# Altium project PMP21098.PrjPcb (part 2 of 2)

## Sheet PMP21098_BlankSheet.SchDoc
size 431 x 279 mm; Date: Not shown in title block; ApprovedBy: Not shown in title block; CheckedBy: Not shown in title block; Author: Not shown in title block; CompanyName: Not shown in title block; Engineer: Not shown in title block; Organization: Not shown in title block; Address1: Not shown in title block; Address2: Not shown in title block; Address3: Not shown in title block; Address4: Not shown in title block; DocumentNumber: 2; Revision: Use project parameter SCH_Rev; SheetNumber: 2; SheetTotal: 3; PageSetup: Record=PageOptions¦CenterHorizontal=True¦CenterVertical=True¦PrintScale=1.00¦XCorrection=1.00¦YCorrection=1.00¦PrintKind=0¦BorderSize=5000000¦LeftOffset=0¦BottomOffset=0¦Orientation=2¦PaperLength=1000¦PaperWidth=1000¦Scale=100¦PaperSource=15¦PrintQuality=600¦MediaType=1¦DitherType=10¦PaperKind=Letter¦PrintScaleMode=1

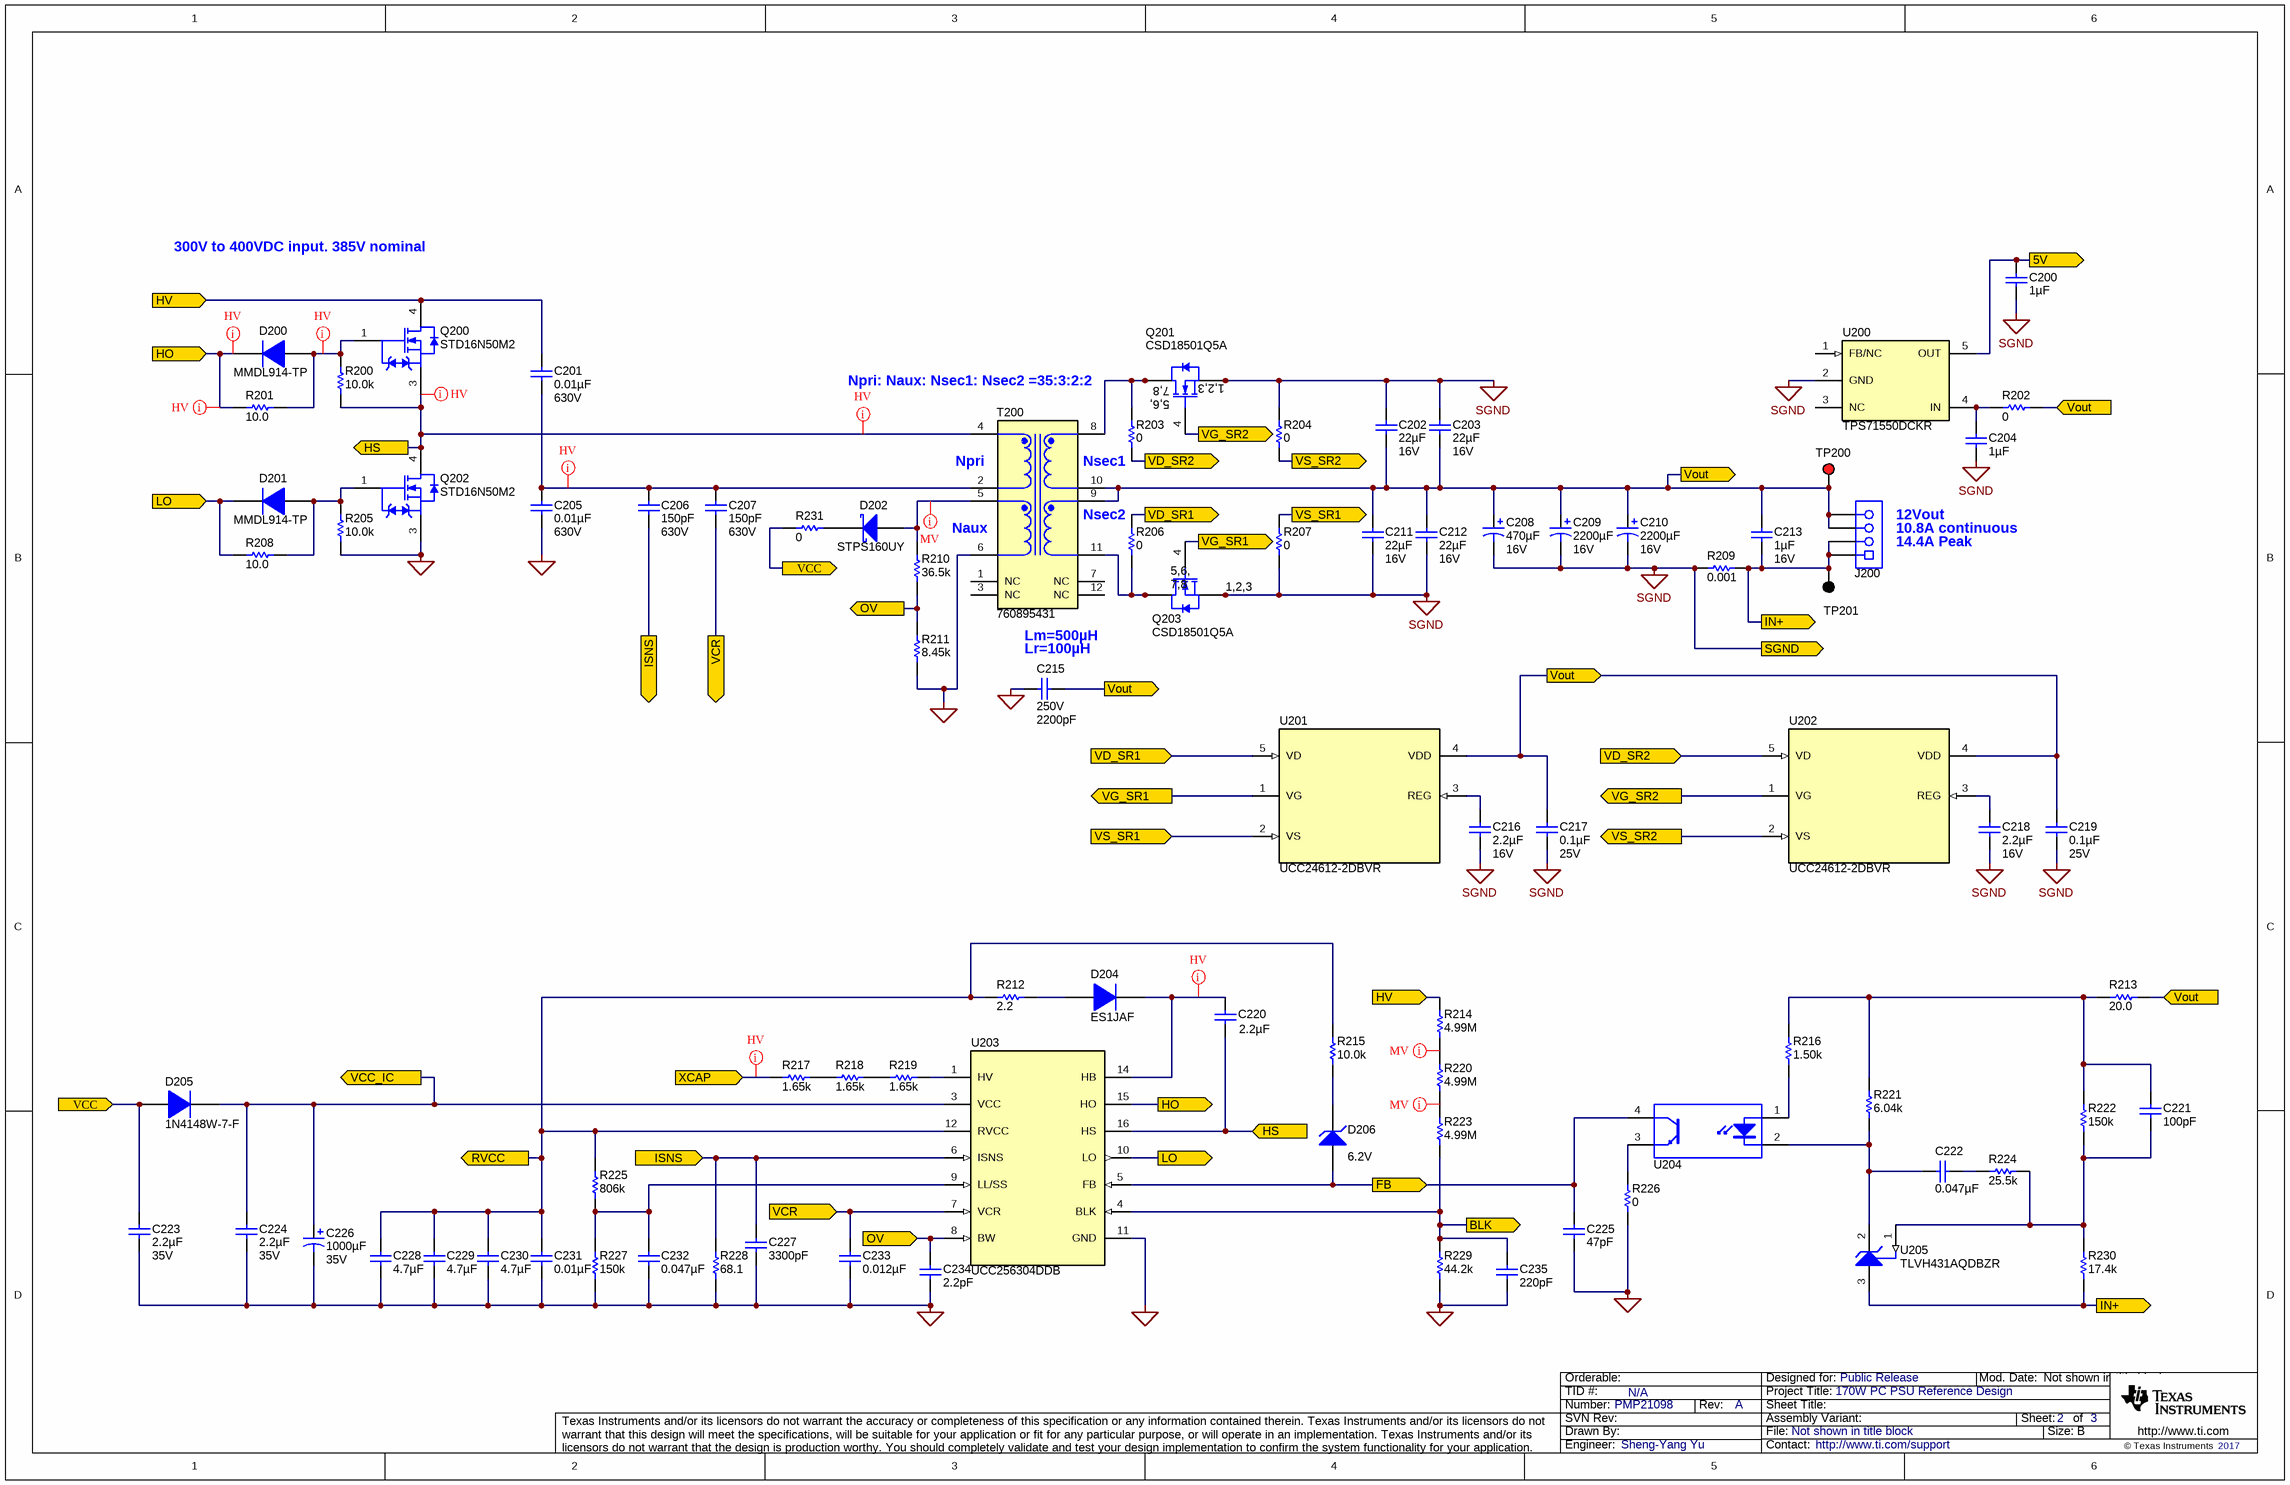
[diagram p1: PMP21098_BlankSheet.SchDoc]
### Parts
C200  ValueDisplayed: 1µF  [0603]  (hidden comment: C0603C105K4PACTU)
C201  ValueDisplayed: 0.01µF  Value2: 630V  [B32021_1300x400x900]  (hidden comment: B32621A6103K189)
C202  ValueDisplayed: 22µF  Value2: 16V  [1206_190]  (hidden comment: EMK316BB7226ML-T)
C203  ValueDisplayed: 22µF  Value2: 16V  [1206_190]  (hidden comment: EMK316BB7226ML-T)
C204  ValueDisplayed: 1µF  [1206]  (hidden comment: GRM319R61E105KC36D)
C205  ValueDisplayed: 0.01µF  Value2: 630V  [B32021_1300x400x900]  (hidden comment: B32621A6103K189)
C206  ValueDisplayed: 150pF  Value2: 630V  [1206]  (hidden comment: GRM31A5C2J151JW01D)
C207  ValueDisplayed: 150pF  Value2: 630V  [1206]  (hidden comment: GRM31A5C2J151JW01D)
C208  ValueDisplayed: 470µF  Value2: 16V  [PS_1000x1250]  (hidden comment: APSC160ELL471MJB5S)
C209  ValueDisplayed: 2200µF  Value2: 16V  [HW_1250x2000]  (hidden comment: EEU-FM1C222)
C210  ValueDisplayed: 2200µF  Value2: 16V  [HW_1250x2000]  (hidden comment: EEU-FM1C222)
C211  ValueDisplayed: 22µF  Value2: 16V  [1206_190]  (hidden comment: EMK316BB7226ML-T)
C212  ValueDisplayed: 22µF  Value2: 16V  [1206_190]  (hidden comment: EMK316BB7226ML-T)
C213  ValueDisplayed: 1µF  Value2: 16V  [0603]  (hidden comment: C0603C105K4PACTU)
C215  VDC_V: 250V  ValueDisplayed: 2200pF  [CAPRD1000W60D1000H1400]  (hidden comment: DE1E3KX222MA5BA01)
C216  ValueDisplayed: 2.2µF  Value2: 16V  [0603]  (hidden comment: 885012106018)
C217  ValueDisplayed: 0.1µF  Value2: 25V  [0603]  (hidden comment: 06033C104JAT2A)
C218  ValueDisplayed: 2.2µF  Value2: 16V  [0603]  (hidden comment: 885012106018)
C219  ValueDisplayed: 0.1µF  Value2: 25V  [0603]  (hidden comment: 06033C104JAT2A)
C220  ValueDisplayed: 2.2µF  [1206]  (hidden comment: C1206C225K4RACTU)
C221  ValueDisplayed: 100pF  [0603]  (hidden comment: 06035A101JAT2A)
C222  ValueDisplayed: 0.047µF  [0603]  (hidden comment: 06033C473JAT2A)
C223  ValueDisplayed: 2.2µF  Value2: 35V  [0603]  (hidden comment: GRM188R6YA225KA12D)
C224  ValueDisplayed: 2.2µF  Value2: 35V  [0603]  (hidden comment: GRM188R6YA225KA12D)
C225  ValueDisplayed: 47pF  [0603]  (hidden comment: GRM1885C1H470FA01J)
C226  ValueDisplayed: 1000µF  Value2: 35V  [B41896_1250x2500]  (hidden comment: EEU-FR1V102B)
C227  ValueDisplayed: 3300pF  [0603]  (hidden comment: GRM1885C1H332JA01D)
C228  ValueDisplayed: 4.7µF  [0603]  (hidden comment: GRM188R61C475KAAJ)
C229  ValueDisplayed: 4.7µF  [0603]  (hidden comment: GRM188R61C475KAAJ)
C230  ValueDisplayed: 4.7µF  [0603]  (hidden comment: GRM188R61C475KAAJ)
C231  ValueDisplayed: 0.01µF  [0603]  (hidden comment: 06031C103JAT2A)
C232  ValueDisplayed: 0.047µF  [0603]  (hidden comment: C1608X7R1H473K080AA)
C233  ValueDisplayed: 0.012µF  [0603]  (hidden comment: C0603C123J3GACTU)
C234  ValueDisplayed: 2.2pF  [0603]  (hidden comment: 06035A2R2CAT2A)
C235  ValueDisplayed: 220pF  [0603]  (hidden comment: GRM188R71H221KA01D)
D200  MMDL914-TP  [SOD-323]
D201  MMDL914-TP  [SOD-323]
D202  STPS160UY  [SMB]
D204  ES1JAF  [SMAF]
D205  1N4148W-7-F  [SOD-123]
D206  value 6.2V  [SOD-123]  (hidden comment: MMSZ5234B-7-F)
J200  ED120/4DS  [On-Shore_ED120_4DS]  (value not drawn)
Q200  STD16N50M2  [DPAK]
Q201  CSD18501Q5A  [DQJ0008A]
Q202  STD16N50M2  [DPAK]
Q203  CSD18501Q5A  [DQJ0008A]
R200  ValueDisplayed: 10.0k  [0805_HV]  (hidden comment: CRCW080510K0FKEA)
R201  ValueDisplayed: 10.0  [0603]  (hidden comment: CRCW060310R0FKEA)
R202  ValueDisplayed: 0  [0603]  (hidden comment: CRCW06030000Z0EA)
R203  ValueDisplayed: 0  [0402]  (hidden comment: CRCW04020000Z0ED)
R204  ValueDisplayed: 0  [0402]  (hidden comment: CRCW04020000Z0ED)
R205  ValueDisplayed: 10.0k  [0805_HV]  (hidden comment: CRCW080510K0FKEA)
R206  ValueDisplayed: 0  [0402]  (hidden comment: CRCW04020000Z0ED)
R207  ValueDisplayed: 0  [0402]  (hidden comment: CRCW04020000Z0ED)
R208  ValueDisplayed: 10.0  [0603]  (hidden comment: CRCW060310R0FKEA)
R209  ValueDisplayed: 0.001  [2010]  (hidden comment: CSNL2010FT1L00)
R210  ValueDisplayed: 36.5k  [0603]  (hidden comment: CRCW060336K5FKEA)
R211  ValueDisplayed: 8.45k  [0603]  (hidden comment: RC0603FR-078K45L)
R212  ValueDisplayed: 2.2  [0603]  (hidden comment: CRCW06032R20JNEA)
R213  ValueDisplayed: 20.0  [0603]  (hidden comment: CRCW060320R0FKEA)
R214  ValueDisplayed: 4.99M  [1206]  (hidden comment: CRCW12064M99FKEA)
R215  ValueDisplayed: 10.0k  [0603]  (hidden comment: ERJ-3EKF1002V)
R216  ValueDisplayed: 1.50k  [0603]  (hidden comment: CRCW06031K50FKEA)
R217  ValueDisplayed: 1.65k  [1206]  (hidden comment: CRCW12061K65FKEA)
R218  ValueDisplayed: 1.65k  [1206]  (hidden comment: CRCW12061K65FKEA)
R219  ValueDisplayed: 1.65k  [1206]  (hidden comment: CRCW12061K65FKEA)
R220  ValueDisplayed: 4.99M  [1206]  (hidden comment: CRCW12064M99FKEA)
R221  ValueDisplayed: 6.04k  [0603]  (hidden comment: CRCW06036K04FKEA)
R222  ValueDisplayed: 150k  [0603]  (hidden comment: CRCW0603150KFKEA)
R223  ValueDisplayed: 4.99M  [1206]  (hidden comment: CRCW12064M99FKEA)
R224  ValueDisplayed: 25.5k  [0603]  (hidden comment: CRCW060325K5FKEA)
R225  ValueDisplayed: 806k  [0603]  (hidden comment: CRCW0603806KFKEA)
R226  ValueDisplayed: 0  [0603]  (hidden comment: CRCW06030000Z0EA)
R227  ValueDisplayed: 150k  [0603]  (hidden comment: CRCW0603150KFKEA)
R228  ValueDisplayed: 68.1  [0603]  (hidden comment: CRCW060368R1FKEA)
R229  ValueDisplayed: 44.2k  [0603]  (hidden comment: CRCW060344K2FKEA)
R230  ValueDisplayed: 17.4k  [0603]  (hidden comment: CRCW060317K4FKEA)
R231  ValueDisplayed: 0  [5108]  (hidden comment: 5108)
T200  760895431  [Wurth_ETD34]
TP200  5000  [Keystone5000]  (value not drawn)
TP201  5001  [Keystone5001]  (value not drawn)
U200  TPS71550DCKR  [DCK0005A_N]
U201  UCC24612-2DBVR  [DBV0005A_N]
U202  UCC24612-2DBVR  [DBV0005A_N]
U203  UCC256304DDB  [DDB0014A]
U204  VO618A-3  [DIP-4]  (value not drawn)
U205  TLVH431AQDBZR  [DBZ0003A_N]

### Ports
5V (out), BLK (out), FB (out), HO (in), HO (out), HS, HS (in), HV (in), IN+ (out), ISNS (in), ISNS (out), LO (in), LO (out), OV (in), OV (out), RVCC (out), SGND (out), VCC (in), VCC (out), VCC_IC (out), VCR (in), VCR (out), VD_SR1 (in), VD_SR1 (out), VD_SR2 (in), VD_SR2 (out), VG_SR1 (out), VG_SR2 (out), Vout, Vout (in), Vout (out), VS_SR1 (in), VS_SR1 (out), VS_SR2 (out), XCAP (in)

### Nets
GND: C205.2 C215.2 C223.1 C224.1 C225.2 C226.2(-) C227.1 C228.2 C229.2 C230.2 C231.2 C232.2 C233.2 C234.2 C235.2 Q202.3(S) R205.1 R211.1 R226.1 R227.1 R228.1 R229.1 T200.6 U203.11(GND)
SGND: C200.2 C202.1 C203.1 C204.2 C208.2(-) C209.2(-) C210.2(-) C211.2 C212.2 C216.2 C217.2 C218.2 C219.2 Q201.1(S) Q201.2(S) Q201.3(S) Q203.1(S) Q203.2(S) Q203.3(S) R204.2 R207.1 R209.1 U200.2(GND) ; port SGND
5V: C200.1 U200.5(OUT) ; port 5V
BLK: C235.1 R223.1 R229.2 U203.4(BLK) ; port BLK
FB: C225.1 D206.2(A) U203.5(FB) U204.4(C) ; port FB
HO: D200.1(K) R201.1 U203.15(HO) ; port HO
HS: C220.2 Q200.3(S) Q202.4(D) R200.1 T200.4 U203.16(HS) ; port HS
HV: C201.1 Q200.4(D) R214.2 ; port HV
IN+: C213.1 J200.1 J200.2 R209.2 R230.1 TP201.1 U205.3(ANODE) ; port IN+
ISNS: C206.1 C227.2 R228.2 U203.6(ISNS) ; port ISNS
LO: D201.1(K) R208.1 U203.10(LO) ; port LO
OV: C234.1 R210.1 R211.2 U203.8(BW) ; port OV
RVCC: C228.1 C229.1 C230.1 C231.1 R212.1 R215.2 R225.2 U203.12(RVCC) ; port RVCC
VCC: C223.2 D205.2(A) R231.1 ; port VCC
VCC_IC: C224.2 C226.1(+) D205.1(K) U203.3(VCC) ; port VCC_IC
VCR: C207.2 C233.1 U203.7(VCR) ; port VCR
VD_SR1: R206.2 U201.5(VD) ; port VD_SR1
VD_SR2: R203.1 U202.5(VD) ; port VD_SR2
VG_SR1: Q203.4(G) U201.1(VG) ; port VG_SR1
VG_SR2: Q201.4(G) U202.1(VG) ; port VG_SR2
Vout: C202.2 C203.2 C208.1(+) C209.1(+) C210.1(+) C211.1 C212.1 C213.2 C215.1 C217.1 C219.1 J200.3 J200.4 R202.2 R213.1 T200.9 T200.10 TP200.1 U201.4(VDD) U202.4(VDD) ; port Vout
VS_SR1: R207.2 U201.2(VS) ; port VS_SR1
VS_SR2: R204.1 U202.2(VS) ; port VS_SR2
XCAP: R217.2 ; port XCAP
NetC201_2: C201.2 C205.1 C206.2 C207.1 T200.2
NetC204_1: C204.1 R202.1 U200.4(IN)
NetC216_1: C216.1 U201.3(REG)
NetC218_1: C218.1 U202.3(REG)
NetC220_1: C220.1 D204.1(K) U203.14(HB)
NetC221_1: C221.1 R213.2 R216.2 R221.2 R222.2
NetC221_2: C221.2 R222.1 R224.2 R230.2 U205.1(REF)
NetC222_1: C222.1 R224.1
NetC222_2: C222.2 R221.1 U204.2(K) U205.2(CATHODE)
NetC232_1: C232.1 R225.1 R227.2 U203.9(LL/SS)
NetD200_2: D200.2(A) Q200.1(G) R200.2 R201.2
NetD201_2: D201.2(A) Q202.1(G) R205.2 R208.2
NetD202_1: D202.1(K) R231.2
NetD202_2: D202.2(A) R210.2 T200.5
NetD204_2: D204.2(A) R212.2
NetD206_1: D206.1(K) R215.1
NetQ201_5: Q201.5(D) Q201.6(D) Q201.7(D) Q201.8(D) Q201.9(D) R203.2 T200.8
NetQ203_5: Q203.5(D) Q203.6(D) Q203.7(D) Q203.8(D) Q203.9(D) R206.1 T200.11
NetR214_1: R214.1 R220.2
NetR216_1: R216.1 U204.1(A)
NetR217_1: R217.1 R218.2
NetR218_1: R218.1 R219.2
NetR219_1: R219.1 U203.1(HV)
NetR220_1: R220.1 R223.2
NetR226_2: R226.2 U204.3(E)

Not connected (* = marked no-connect by the designer): T200 1(NC) 3(NC) 7(NC) 12(NC); U200 1(FB/NC) 3(NC)

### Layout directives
net class HV: HO, HS, NetC201_2, NetC220_1, NetD200_2, XCAP
net class MV: NetD202_2, NetR214_1, NetR220_1

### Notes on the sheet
- 300V to 400VDC input. 385V nominal
- Npri: Naux: Nsec1: Nsec2 =35:3:2:2
- (near T200) Npri
- Nsec1
- (near T200) Naux
- Nsec2
- (near J200) 12Vout
- (near J200) 10.8A continuous
- (near J200) 14.4A Peak
- Lm=500µH
- Lr=100µH

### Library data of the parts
C200 C213 = C0603C105K4PACTU: CAP, CERM, 1uF, 16V, +/-10%, X5R, 0603; Manufacturer: Kemet; Polarized: N; CompType: Capacitor; U/M: EA; Cap_F: 0.000001; Tolerance_%: 10; Value1: Unknown; VDC_V: 16; TaMin_C: -55; TaMax_C: 85
C201 C205 = B32021A3332M289: CAP FILM 10000PF 10% 630VDC RAD; Manufacturer: EPCOS (TDK); Polarized: N; CompType: Capacitor; Value: 0.01uF; U/M: EA; Tolerance_%: 20; Value1: Unknown; VDC_V: 630; TaMin_C: -40; TaMax_C: 110; SizeAreaWB_mm2: 90; SizeArea_mm2: 52; SizeX_mm: 13; SizeY_mm: 4; SizeZ_mm: 9; AEC Category: Q200; AEC Qualified: Y; AEC Grade: 2
C202 C203 C211 C212 = EMK316BB7226ML-T: CAP, CERM, 22 µF, 16 V,+/- 20%, X7R, 1206; Manufacturer: Taiyo Yuden; Polarized: N; CompType: Capacitor; Value: 22uF; U/M: EA; Cap_F: 0.000022; Tolerance_%: 20; VDC_V: 16; TaMin_C: -55; TaMax_C: 125; Cap_Case: 1206; SizeArea_mm2: 5.12; SizeAreaWB_mm2: 10.92; SizeX_mm: 3.2; SizeY_mm: 1.6; SizeZ_mm: 1.9; AEC Category: Q200
C204 = GRM319R61E105KC36D: CAP, CERM, 1 µF, 25 V,+/- 10%, X5R, 1206; Manufacturer: MuRata; Polarized: N; CompType: Capacitor; Value: 1uF; U/M: EA; Cap_F: 0.000001; Tolerance_%: 10; ESR_ohm: 0.01; Value1: 0.01 ohm; VDC_V: 25; Value2: 25V; TaMin_C: -55; TaMax_C: 85; SizeArea_mm2: 5.12; SizeAreaWB_mm2: 10.92; SizeX_mm: 3.2; SizeY_mm: 1.6; SizeZ_mm: 1.35; AEC Category: Q200
C206 = GRM31A5C2J151JW01D: CAP, CERM, 150 pF, 630 V, +/- 5%, C0G/NP0, 1206; Manufacturer: MuRata; Polarized: N; CompType: Capacitor; Value: 150pF; U/M: EA; Cap_F: 0.00000000015; Tolerance_%: 5; Value1: Unknown; VDC_V: 630; TaMin_C: -55; TaMax_C: 125; SizeArea_mm2: 5.12; SizeAreaWB_mm2: 10.92; SizeX_mm: 3.2; SizeY_mm: 1.6; SizeZ_mm: 1.35; AEC Category: Q200
C207 = GRM31A5C2J151JW01D: CAP, CERM, 150 pF, 630 V,+/- 5%, C0G/NP0, 1206; Manufacturer: MuRata; Polarized: N; CompType: Capacitor; Value: 150pF; U/M: EA; Cap_F: 0.00000000015; Tolerance_%: 5; VDC_V: 630; TaMin_C: -55; TaMax_C: 125; SizeArea_mm2: 5.12; SizeAreaWB_mm2: 10.92; SizeX_mm: 3.2; SizeY_mm: 1.6; SizeZ_mm: 1.35; AEC Category: Q200
C208 = APS-160ELL331MJC5S: CAP ALUM POLY 470UF 20% 16V T/H; Manufacturer: Chemi-Con; Polarized: Y; CompType: Capacitor; U/M: EA; Cap_F: 0.00033; Tolerance_%: 20; Value1: 0.014 ohm; VDC_V: 16; ESR_ohm: 0.014; IRMS_A: 5.05; TaMin_C: -55; TaMax_C: 105; SizeAreaWB_mm2: 144; SizeArea_mm2: 100; SizeX_mm: 10; SizeZ_mm: 14; AEC Category: Q200; Green_Lifecycle: Active; Green_REACh: Passed
C209 C210 = UHW1C222MHD: CAP ALUM 2200UF 20% 16V RADIAL; Manufacturer: Panasonic; Polarized: Y; CompType: Capacitor; Cap_F: 0.0022; Tolerance_%: 20; VDC_V: 16; ESR_ohm: 0.016; IRMS_A: 2.6; TaMin_C: -40; TaMax_C: 105; Cap_Case: 12.5x20mm; SizeAreaWB_mm2: 210.25; SizeArea_mm2: 156.25; SizeX_mm: 12.5; SizeZ_mm: 22; AEC Category: Q200
C215 = CMP-0009602-2: CAP, CERM, 2200 pF, 250 V, +/- 20%, E, Disc 10x8mm; Manufacturer: MuRata; TaMin_C: -25°C; Polarized: N; SizeAreaWB_mm2: 120; Value1: Unknown; U/M: EA; Value: 2200pF; TaMax_C: 85°C; SizeZ_mm: 14; SizeX_mm: 10; SizeY_mm: 8; SizeArea_mm2: 80; CompType: Capacitor; Cap_F: 2.2nF; AEC Category: Q200
C216 C218 = 885012106018: CAP, CERM, 2.2 µF, 16 V,+/- 20%, X5R, 0603; Manufacturer: Wurth Elektronik; Polarized: N; CompType: Capacitor; Value: 2.2uF; U/M: EA; Cap_F: 0.0000022; Tolerance_%: 20; VDC_V: 16; TaMin_C: -55; TaMax_C: 85; SizeArea_mm2: 1.28; SizeAreaWB_mm2: 4.68; SizeX_mm: 1.6; SizeY_mm: 0.8; SizeZ_mm: 1; AEC Category: Q200; Green_Lifecycle: Not Set; Green_REACh: Incomplete
C217 C219 = 06033C104JAT2A: CAP, CERM, 0.1 µF, 25 V,+/- 5%, X7R, 0603; Manufacturer: AVX; Polarized: N; CompType: Capacitor; Value: 0.1uF; U/M: EA; Cap_F: 0.0000001; Tolerance_%: 5; ESR_ohm: 0.05; Value1: 0.05 ohm; VDC_V: 25; TaMin_C: -55; TaMax_C: 125; SizeArea_mm2: 1.28; SizeAreaWB_mm2: 4.68; SizeX_mm: 1.6; SizeY_mm: 0.8; SizeZ_mm: 1; AEC Category: Q200; Green_Lifecycle: Active; Green_REACh: Passed
C220 = C1206C225K4RACTU: CAP, CERM, 2.2 µF, 16 V, +/- 10%, X7R, 1206; Manufacturer: Kemet; Polarized: N; CompType: Capacitor; Value: 2.2uF; U/M: EA; Cap_F: 0.0000022; Tolerance_%: 10; ESR_ohm: 0.009; Value1: 0.009 ohm; VDC_V: 16; Value2: 16V; IRMS_A: 4.46; TaMin_C: -55; TaMax_C: 125; AEC Category: Q200; SizeArea_mm2: 5.12; SizeAreaWB_mm2: 10.92; SizeX_mm: 3.2; SizeY_mm: 1.6; SizeZ_mm: 1.35
C221 = 06035A101JAT2A: CAP, CERM, 100 pF, 50 V,+/- 5%, C0G/NP0, 0603; Manufacturer: AVX; Polarized: N; CompType: Capacitor; Value: 100pF; U/M: EA; Cap_F: 0.0000000001; Tolerance_%: 5; ESR_ohm: 0.119; Value1: 0.119 ohm; VDC_V: 50; Value2: 50V; TaMin_C: -55; TaMax_C: 125; SizeArea_mm2: 1.28; SizeAreaWB_mm2: 4.68; SizeX_mm: 1.6; SizeY_mm: 0.8; SizeZ_mm: 1; AEC Category: Q200; Green_Lifecycle: Active; Green_REACh: Passed
C222 = 06033C473JAT2A: CAP, CERM, 0.047 µF, 25 V,+/- 5%, X7R, 0603; Manufacturer: AVX; Polarized: N; CompType: Capacitor; Value: 0.047uF; U/M: EA; Cap_F: 0.000000047; Tolerance_%: 5; ESR_ohm: 0.052; Value1: 0.052 ohm; VDC_V: 25; Value2: 25V; TaMin_C: -55; TaMax_C: 125; SizeArea_mm2: 1.28; SizeAreaWB_mm2: 4.68; SizeX_mm: 1.6; SizeY_mm: 0.8; SizeZ_mm: 1; AEC Category: Q200; Green_Lifecycle: Active; Green_REACh: Passed
C223 C224 = GRM188R6YA225KA12D: CAP, CERM, 2.2 µF, 35 V, +/- 10%, X5R, 0603; Manufacturer: MuRata; Polarized: N; CompType: Capacitor; Value: 2.2uF; U/M: EA; Cap_F: 0.0000022; Tolerance_%: 10; Value1: Unknown; VDC_V: 35; TaMin_C: -55; TaMax_C: 85; AEC Category: Q200
C225 = GRM1885C1H470FA01J: CAP, CERM, 47 pF, 50 V, +/- 1%, C0G/NP0, 0603; Manufacturer: MuRata; Polarized: N; CompType: Capacitor; Value: 47pF; U/M: EA; Cap_F: 0.000000000047; Tolerance_%: 1; Value1: Unknown; VDC_V: 50; Value2: 50V; TaMin_C: -55; TaMax_C: 125; AEC Category: Q200
C226 = B41896C7687M000: CAP ALUM 1000UF 20% 35V RADIAL; Manufacturer: Panasonic; Polarized: Y; CompType: Capacitor; U/M: EA; Cap_F: 0.00068; Tolerance_%: 20; Value1: 0.041 ohm; VDC_V: 35; ESR_ohm: 0.041; IRMS_A: 2.28; TaMin_C: -55; TaMax_C: 125; Cap_Case: 12.5x25mm; SizeAreaWB_mm2: 210.25; SizeArea_mm2: 156.25; SizeX_mm: 12.5; SizeZ_mm: 27; AEC Category: Q200; AEC Grade: 1; Green_Lifecycle: Not Set; Green_REACh: Incomplete
C227 = GRM1885C1H332JA01D: CAP, CERM, 3300 pF, 50 V, +/- 5%, C0G/NP0, 0603; Manufacturer: MuRata; Polarized: N; CompType: Capacitor; Value: 3300pF; U/M: EA; Cap_F: 0.0000000033; Tolerance_%: 5; Value1: Unknown; VDC_V: 50; Value2: 50V; TaMin_C: -55; TaMax_C: 125; SizeArea_mm2: 1.28; SizeAreaWB_mm2: 4.68; SizeX_mm: 1.6; SizeY_mm: 0.8; SizeZ_mm: 1; AEC Category: Q200
C228-C230 = GRM188R61C475KAAJ: CAP, CERM, 4.7 µF, 16 V, +/- 10%, X5R, 0603; Manufacturer: MuRata; Polarized: N; CompType: Capacitor; Value: 4.7uF; U/M: EA; Cap_F: 0.0000047; Tolerance_%: 10; Value1: Unknown; VDC_V: 16; Value2: 16V; TaMin_C: -55; TaMax_C: 85; AEC Category: Q200
C231 = 06031C103JAT2A: CAP, CERM, 0.01 µF, 100 V,+/- 5%, X7R, 0603; Manufacturer: AVX; Polarized: N; CompType: Capacitor; Value: 0.01uF; U/M: EA; Cap_F: 0.00000001; Tolerance_%: 5; ESR_ohm: 0.098; Value1: 0.098 ohm; VDC_V: 100; Value2: 100V; TaMin_C: -55; TaMax_C: 125; SizeArea_mm2: 1.28; SizeAreaWB_mm2: 4.68; SizeX_mm: 1.6; SizeY_mm: 0.8; SizeZ_mm: 1; AEC Category: Q200; Green_Lifecycle: Active; Green_REACh: Passed
C232 = C1608X7R1H473K080AA: CAP, CERM, 0.047 µF, 50 V,+/- 10%, X7R, 0603; Manufacturer: TDK; Polarized: N; CompType: Capacitor; Value: 0.047uF; U/M: EA; Cap_F: 0.000000047; Tolerance_%: 10; ESR_ohm: 0.049007; Value1: 0.049007 ohm; VDC_V: 50; Value2: 50V; IRMS_A: 0.767528; TaMin_C: -55; TaMax_C: 125; SizeArea_mm2: 1.28; SizeAreaWB_mm2: 4.68; SizeX_mm: 1.6; SizeY_mm: 0.8; SizeZ_mm: 1; AEC Category: Q200; Green_Lifecycle: NRND; Green_REACh: Passed
C233 = C0603C123J3GACTU: CAP, CERM, 0.012 µF, 25 V,+/- 5%, C0G/NP0, 0603; Manufacturer: Kemet; Polarized: N; CompType: Capacitor; Value: 0.012uF; U/M: EA; Cap_F: 0.000000012; Tolerance_%: 5; VDC_V: 25; Value2: 25V; TaMin_C: -55; TaMax_C: 125; SizeArea_mm2: 1.28; SizeAreaWB_mm2: 4.68; SizeX_mm: 1.6; SizeY_mm: 0.8; SizeZ_mm: 1; AEC Category: Q200; Green_Lifecycle: Not Set; Green_REACh: Incomplete
C234 = 06035A2R2CAT2A: CAP, CERM, 2.2 pF, 50 V, +/- 11%, C0G/NP0, 0603; Manufacturer: AVX; Polarized: N; CompType: Capacitor; Value: 2.2pF; U/M: EA; Cap_F: 0.0000000000022; Tolerance_%: 11; ESR_ohm: 1.033; Value1: 1.033 ohm; VDC_V: 50; Value2: 50V; TaMin_C: -55; TaMax_C: 125; SizeArea_mm2: 1.28; SizeAreaWB_mm2: 4.68; SizeX_mm: 1.6; SizeY_mm: 0.8; SizeZ_mm: 1; AEC Category: Q200
C235 = GRM188R71H221KA01D: CAP, CERM, 220 pF, 50 V, +/- 10%, X7R, 0603; Manufacturer: MuRata; Polarized: N; CompType: Capacitor; Value: 220pF; U/M: EA; Cap_F: 0.00000000022; Tolerance_%: 10; Value1: Unknown; VDC_V: 50; Value2: 50V; TaMin_C: -55; TaMax_C: 125; AEC Category: Q200
D200 D201 = MMDL914-TP: Diode, Switching, 100 V, 0.2 A, SOD-323; Manufacturer: Micro Commercial Components; U/M: EA; Vf_V: 1; Value: 100V; Value1: 0.2A; Value2: 1V; Io_A: 0.2; Vr_V: 100; TJmax_C: 150; SizeAreaWB_mm2: 8.695; SizeArea_mm2: 3.645; SizeX_mm: 2.7; SizeY_mm: 1.35; AEC Category: Q101
D202 = STPS160UY: Diode, Schottky, 60 V, 1 A, AEC-Q101, SMB; Manufacturer: STMicroelectronics; U/M: EA; Vf_V: 0.67; Value: 60V; Value1: 1A; Value2: 0.67V; Io_A: 1; Vr_V: 60; TJmax_C: 150; AEC Category: Q101; AEC Qualified: Y; SizeAreaWB_mm2: 44.156; SizeArea_mm2: 21.336; SizeX_mm: 5.6; SizeY_mm: 3.81; SizeZ_mm: 2.6
D204 = ES1JAF: Diode, Ultrafast, 600 V, 1 A, AEC-Q101, SMAF; Manufacturer: Fairchild Semiconductor; U/M: EA; Vf_V: 1.7; Value: 600V; Value1: 1A; Value2: 1.7V; Io_A: 1; Vr_V: 600; TJmax_C: 150; AEC Category: Q101; AEC Qualified: Y
D205 = 1N4148W-7-F: Diode, Ultrafast, 100 V, 0.15 A, SOD-123; Manufacturer: Diodes Inc.; U/M: EA; Vf_V: 1.25; Value: 100V; Value1: 0.15A; Value2: 1.25V; Io_A: 0.15; Vr_V: 100; TJmax_C: 150; SizeAreaWB_mm2: 13.095; SizeArea_mm2: 6.545; SizeX_mm: 3.85; SizeY_mm: 1.7; SizeZ_mm: 1.35; AEC Category: Q101
D206 = MMSZ5234B-7-F: Diode, Zener, 6.2 V, 500 mW, SOD-123; Manufacturer: Diodes Inc.; SymbolCreator: a0412235; U/M: EA; Power_W: 0.5; Vz_V: 6.2; Value1: 0.5W; RJA_CperW: 350; SizeAreaWB_mm2: 13.095; SizeArea_mm2: 6.545; SizeX_mm: 3.85; SizeY_mm: 1.7; SizeZ_mm: 1.35; AEC Category: Q101
J200 = ED120/4DS: Terminal Block, 5.08 mm, 4x1, Brass, TH; Manufacturer: On-Shore Technology; SymbolCreator: a0411947; Pitch_mm: 5.08; Gender: Female; Shrouded: N; Row_Count: 1; Current_A: 15; Voltage_V: 300; Cert_CULUS: Y
Q200 Q202 = STD16N50M2: MOSFET, N-CH, 550 V, 13 A, DPAK; Manufacturer: STMicroelectronics; Alternate Manufacturer: None; SymbolCreator: Altium; U/M: EA; ChType: N; Value: 550V; VdsMax_V: 550; Value1: ? ohm; Value2: 19.5 nC; QgTyp_nC: 19.5; Vgs_V: 25; IdsMax_A: 13; SizeAreaWB_mm2: 101.7114; SizeArea_mm2: 64.8114; SizeX_mm: 9.91; SizeY_mm: 6.54; SizeZ_mm: 2.29; AEC Category: Q101; Green_Lifecycle: Active; Green_REACh: Passed
Q201 Q203 = CSD18501Q5A: MOSFET, N-CH, 40 V, 22 A, DQJ0008A (VSONP-8); Manufacturer: Texas Instruments; Alternate Manufacturer: None; U/M: EA; ChType: N; Value: 40V; VdsMax_V: 40; Value1: 0.0043 ohm; Rdson45_ohm: 0.0043; Value2: 20 nC; QgTyp_nC: 20; IdsMax_A: 22; SizeAreaWB_mm2: 55.2; SizeArea_mm2: 29.4; SizeX_mm: 6; SizeY_mm: 4.9; SizeZ_mm: 1.1; AEC Category: Q101
R200 R205 = CRCW080510K0FKEA: RES, 10.0 k, 1%, 0.125 W, 0805; Manufacturer: Vishay-Dale; CompType: Resistor; Value: 10.0k; Res_ohm: 10000; Value_Code: 10k0; Tolerance_%: 1; Power_W: 0.125; Value2: 0.125W; VDC_V: 150; TempCo: 100 ppm/C; SizeArea_mm2: 2.5; SizeX_mm: 2; SizeY_mm: 1.25; SizeZ_mm: 1.45; EIA_Code: E96; U/M: EA; AEC Category: Q200
R201 R208 = CRCW060310R0FKEA: RES, 10.0, 1%, 0.1 W, 0603; Manufacturer: Vishay-Dale; CompType: Resistor; Value: 10.0; Res_ohm: 10; Value_Code: 10R0; Tolerance_%: 1; Power_W: 0.1; Value2: 0.1W; VDC_V: 75; TempCo: 100 ppm/C; SizeArea_mm2: 1.28; SizeX_mm: 1.6; SizeY_mm: 0.8; EIA_Code: E96; U/M: EA; AEC Category: Q200
R202 R226 = CRCW06030000Z0EA: RES, 0, 5%, 0.1 W, 0603; Manufacturer: Vishay-Dale; CompType: Resistor; Value: 0; Value_Code: 0000; Tolerance_%: 5; Power_W: 0.1; Value2: 0.1W; VDC_V: 75; TempCo: 200 ppm/C; SizeArea_mm2: 1.28; SizeX_mm: 1.6; SizeY_mm: 0.8; SizeZ_mm: 1; EIA_Code: E24; U/M: EA; AEC Category: Q200; Green_Lifecycle: Active; Green_REACh: Passed
R203 R204 R206 R207 = CRCW04020000Z0ED: RES, 0, 5%, 0.063 W, 0402; Manufacturer: Vishay-Dale; CompType: Resistor; Value: 0; Value_Code: 0000; Tolerance_%: 5; Power_W: 0.063; Value2: 0.063W; VDC_V: 50; TempCo: 200 ppm/C; SizeArea_mm2: 0.5; SizeX_mm: 1; SizeZ_mm: 0.6; EIA_Code: E24; U/M: EA; AEC Category: Q200; Green_Lifecycle: Active; Green_REACh: Passed
R209 = CSNL2010FT1L00: RES, 0.001, 1%, 1.5 W, 2010; Manufacturer: Stackpole Electronics Inc; CompType: Resistor; Value: 0.001; Value_Code: 1L000; Tolerance_%: 1; Power_W: 1.5; Value2: 1.5W; TempCo: 50 ppm/C; SizeArea_mm2: 12.5; SizeX_mm: 5; SizeY_mm: 2.5; SizeZ_mm: 1.66; EIA_Code: E96; U/M: EA; AEC Category: Q200
R210 = CRCW060336K5FKEA: RES, 36.5 k, 1%, 0.1 W, 0603; Manufacturer: Vishay-Dale; CompType: Resistor; Value: 36.5k; Res_ohm: 36500; Value_Code: 36k5; Tolerance_%: 1; Power_W: 0.1; Value2: 0.1W; VDC_V: 75; TempCo: 100 ppm/C; SizeArea_mm2: 1.28; SizeX_mm: 1.6; SizeY_mm: 0.8; EIA_Code: E96; U/M: EA; AEC Category: Q200
R211 = RC0603FR-078K45L: RES, 8.45 k, 1%, 0.1 W, 0603; Manufacturer: Yageo America; CompType: Resistor; Value: 8.45k; Res_ohm: 8450; Value_Code: 8k45; Tolerance_%: 1; Power_W: 0.1; Value2: 0.1W; VDC_V: 150; TempCo: 200 ppm/C; SizeArea_mm2: 1.28; SizeX_mm: 1.6; SizeY_mm: 0.8; EIA_Code: E96; U/M: EA; AEC Category: Q200; AEC Qualified: N; Green_Lifecycle: Active; Green_REACh: Passed
R212 = CRCW06032R20JNEA: RES, 2.2, 5%, 0.1 W, 0603; Manufacturer: Vishay-Dale; CompType: Resistor; Value: 2.2; Value_Code: 2R20; Tolerance_%: 5; Power_W: 0.1; Value2: 0.1W; VDC_V: 75; TempCo: 200 ppm/C; EIA_Code: E24; U/M: EA
R213 = CRCW060320R0FKEA: RES, 20.0, 1%, 0.1 W, 0603; Manufacturer: Vishay-Dale; CompType: Resistor; Value: 20.0; Res_ohm: 20; Value_Code: 20R0; Tolerance_%: 1; Power_W: 0.1; Value2: 0.1W; VDC_V: 75; TempCo: 100 ppm/C; SizeArea_mm2: 1.28; SizeX_mm: 1.6; SizeY_mm: 0.8; EIA_Code: E96; U/M: EA; AEC Category: Q200; Green_Lifecycle: Active; Green_REACh: Passed
R214 R220 R223 = CRCW12064M99FKEA: RES, 4.99 M, 1%, 0.25 W, 1206; Manufacturer: Vishay-Dale; CompType: Resistor; Value: 4.99Meg; Res_ohm: 4990000; Value_Code: 4M99; Tolerance_%: 1; Power_W: 0.25; Value2: 0.25W; VDC_V: 200; TempCo: 100 ppm/C; EIA_Code: E96; U/M: EA; AEC Category: Q200; SizeArea_mm2: 5.12; SizeX_mm: 3.2; SizeY_mm: 1.6; SizeZ_mm: 1.35
R215 = ERJ-3EKF1002V: RES, 10.0 k, 1%, 0.1 W, 0603; Manufacturer: Panasonic; CompType: Resistor; Value: 10.0k; Res_ohm: 10000; Value_Code: 10k0; Tolerance_%: 1; Power_W: 0.1; Value2: 0.1W; VDC_V: 75; TempCo: 100 ppm/C; SizeArea_mm2: 1.28; SizeX_mm: 1.6; SizeY_mm: 0.8; EIA_Code: E96; U/M: EA; AEC Category: Q200; Green_Lifecycle: Active; Green_REACh: Passed
R216 = CRCW06031K50FKEA: RES, 1.50 k, 1%, 0.1 W, 0603; Manufacturer: Vishay-Dale; CompType: Resistor; Value: 1.50k; Res_ohm: 1500; Value_Code: 1k50; Tolerance_%: 1; Power_W: 0.1; Value2: 0.1W; VDC_V: 75; TempCo: 100 ppm/C; SizeArea_mm2: 1.28; SizeX_mm: 1.6; SizeY_mm: 0.8; EIA_Code: E96; U/M: EA; AEC Category: Q200; Green_Lifecycle: Active; Green_REACh: Passed
R217-R219 = CRCW12061K65FKEA: RES, 1.65 k, 1%, 0.25 W, 1206; Manufacturer: Vishay-Dale; CompType: Resistor; Value: 1.65k; Res_ohm: 1650; Value_Code: 1k65; Tolerance_%: 1; Power_W: 0.25; Value2: 0.25W; VDC_V: 200; TempCo: 100 ppm/C; EIA_Code: E96; U/M: EA; AEC Category: Q200; SizeArea_mm2: 5.12; SizeX_mm: 3.2; SizeY_mm: 1.6; SizeZ_mm: 1.35
R221 = CRCW06036K04FKEA: RES, 6.04 k, 1%, 0.1 W, 0603; Manufacturer: Vishay-Dale; CompType: Resistor; Value: 6.04k; Res_ohm: 6040; Value_Code: 6k04; Tolerance_%: 1; Power_W: 0.1; Value2: 0.1W; VDC_V: 75; TempCo: 100 ppm/C; EIA_Code: E96; U/M: EA; AEC Category: Q200
R222 R227 = CRCW0603150KFKEA: RES, 150 k, 1%, 0.1 W, 0603; Manufacturer: Vishay-Dale; CompType: Resistor; Value: 150k; Res_ohm: 150000; Tolerance_%: 1; Power_W: 0.1; Value2: 0.1W; VDC_V: 75; TempCo: 100 ppm/C; SizeArea_mm2: 1.28; SizeX_mm: 1.6; SizeY_mm: 0.8; EIA_Code: E96; U/M: EA; AEC Category: Q200; Green_Lifecycle: Active; Green_REACh: Passed
R224 = CRCW060325K5FKEA: RES, 25.5 k, 1%, 0.1 W, 0603; Manufacturer: Vishay-Dale; CompType: Resistor; Value: 25.5k; Res_ohm: 25500; Value_Code: 25k5; Tolerance_%: 1; Power_W: 0.1; Value2: 0.1W; VDC_V: 75; TempCo: 100 ppm/C; SizeArea_mm2: 1.28; SizeX_mm: 1.6; SizeY_mm: 0.8; EIA_Code: E96; U/M: EA; AEC Category: Q200; Green_Lifecycle: Active; Green_REACh: Passed
R225 = CRCW0603806KFKEA: RES, 806 k, 1%, 0.1 W, 0603; Manufacturer: Vishay-Dale; CompType: Resistor; Value: 806k; Res_ohm: 806000; Tolerance_%: 1; Power_W: 0.1; Value2: 0.1W; VDC_V: 75; TempCo: 100 ppm/C; SizeArea_mm2: 1.28; SizeX_mm: 1.6; SizeY_mm: 0.8; EIA_Code: E96; U/M: EA; AEC Category: Q200; Green_Lifecycle: Active; Green_REACh: Passed
R228 = CRCW060368R1FKEA: RES, 68.1, 1%, 0.1 W, 0603; Manufacturer: Vishay-Dale; CompType: Resistor; Value: 68.1; Value_Code: 68R1; Tolerance_%: 1; Power_W: 0.1; Value2: 0.1W; VDC_V: 75; TempCo: 100 ppm/C; SizeArea_mm2: 1.28; SizeX_mm: 1.6; SizeY_mm: 0.8; EIA_Code: E96; U/M: EA; AEC Category: Q200
R229 = CRCW060344K2FKEA: RES, 44.2 k, 1%, 0.1 W, 0603; Manufacturer: Vishay-Dale; CompType: Resistor; Value: 44.2k; Res_ohm: 44200; Value_Code: 44k2; Tolerance_%: 1; Power_W: 0.1; Value2: 0.1W; VDC_V: 75; TempCo: 100 ppm/C; SizeArea_mm2: 1.28; SizeX_mm: 1.6; SizeY_mm: 0.8; EIA_Code: E96; U/M: EA; AEC Category: Q200; Green_Lifecycle: Active; Green_REACh: Passed
R230 = CRCW060317K4FKEA: RES, 17.4 k, 1%, 0.1 W, 0603; Manufacturer: Vishay-Dale; CompType: Resistor; Value: 17.4k; Res_ohm: 17400; Value_Code: 17k4; Tolerance_%: 1; Power_W: 0.1; Value2: 0.1W; VDC_V: 75; TempCo: 100 ppm/C; SizeArea_mm2: 1.28; SizeX_mm: 1.6; SizeY_mm: 0.8; EIA_Code: E96; U/M: EA; AEC Category: Q200; Green_Lifecycle: Active; Green_REACh: Passed
R231 = 5108: RES, 0, 1%, 0.5 W, 1206; Manufacturer: Keystone; CompType: Resistor; Value: 0; Tolerance_%: 1; Power_W: 0.5; Value2: 0.5W; TempCo: ppm/C; SizeArea_mm2: 5.185; SizeX_mm: 3.05; SizeY_mm: 1.7; SizeZ_mm: 0.84; U/M: EA; AEC Category: Q200; AEC Qualified: N
T200 = CMP-0077669-1: Transformer, 600 uH, TH; Manufacturer: Wurth Elektronik; SizeAreaWB_mm2: 1444.0; SizeArea_mm2: 1296.0; AEC Qualified: N; Ns2toNp: 0.057; Lp: 600.0; AEC Category: Q200; Value: 600uH; SizeZ_mm: 26.0; Ind_H: 600µH; SizeY_mm: 36.0; LeakageInd_H: 100µH; Rsec2_ohm: 3.1m; DCR_ohm: 2.6d
TP200 = 5000: Test Point, Miniature, Red, TH; Manufacturer: Keystone; CompType: Test Point Loop; ContactFinish: Silver
TP201 = 5001: Test Point, Miniature, Black, TH; Manufacturer: Keystone; CompType: Test Point Loop; ContactFinish: Silver; Green_Lifecycle: Active; Green_REACh: Passed
U200 = TPS71533DCKR: 50 mA, 24 V, 3.2-uA Iq, Low-Dropout Linear Regulator in SC70 Package, DCK0005A (SOT-SC70-5); Manufacturer: Texas Instruments; SymbolCreator: a0799628; SizeArea_mm2: 4.2; SizeAreaWB_mm2: 9.3; SizeX_mm: 2.1; SizeY_mm: 2; SizeZ_mm: 1.1; CompType: IC; U/M: EA; Green_Lifecycle: Active; Green_REACh: Passed
U201 U202 = UCC24612-1DBVR: UCC24612-2DBV, DBV0005A (SOT-23-5); Alternate PartNumber: UCC24612-2DBVT; Manufacturer: Texas Instruments; SymbolCreator: Altium; SizeArea_mm2: 8.12; SizeAreaWB_mm2: 14.82; SizeX_mm: 2.8; SizeY_mm: 2.9; SizeZ_mm: 1.45; CompType: IC; U/M: EA
U203 = UCC25630DDB: Enhanced LLC Resonant Controller with Driver, DDB0014A; Manufacturer: Texas Instruments; SymbolCreator: Altium; CompType: IC; U/M: EA
U204 = VO618A: OPTOISOLATOR 5.3KV TRANS 4-DIP; Manufacturer: Vishay-Semiconductor; CTR (Min): 100%; CTR (Max): 200%; Voltage_Isolation_Vrms: 5300V; CompType: Optocoupler; SizeAreaWB_mm2: 71.064; SizeArea_mm2: 40.304; SizeX_mm: 8.8; SizeY_mm: 4.58; SizeZ_mm: 5
U205 = TLVH431AQDBZR: Low-Voltage Adjustable Precision Shunt Regulator, 80 mA, -40 to 125 degC, 3-pin SOT-23 (DBZ), Green (RoHS & no Sb/Br); Manufacturer: Texas Instruments; Alternate PartNumber: Equivalent; Initial Accuracy @ 25/deg C(%): 1; Iout/Iz(Max)(mA): 80; Rating: Catalog; SubFamily: Shunt Voltage Reference; Temp Coeff(Max)(ppm/ degree C): 129; VO Adj(Max)(V): 18; VO Adj(Min)(V): 1.24

## Sheet PMP21098_EVM_Hardware.SchDoc
size 431 x 279 mm; Date: Not shown in title block; ApprovedBy: Not shown in title block; CheckedBy: Not shown in title block; Author: Not shown in title block; CompanyName: Not shown in title block; Engineer: Not shown in title block; Organization: Not shown in title block; Address1: Not shown in title block; Address2: Not shown in title block; Address3: Not shown in title block; Address4: Not shown in title block; DocumentNumber: 3; Revision: Use project parameter SCH_Rev; SheetNumber: 3; SheetTotal: 3; PageSetup: Record=PageOptions¦CenterHorizontal=True¦CenterVertical=True¦PrintScale=1.00¦XCorrection=1.00¦YCorrection=1.00¦PrintKind=0¦BorderSize=5000000¦LeftOffset=0¦BottomOffset=0¦Orientation=2¦PaperLength=1000¦PaperWidth=1000¦Scale=100¦PaperSource=15¦PrintQuality=600¦MediaType=1¦DitherType=10¦PaperKind=Letter¦PrintScaleMode=1

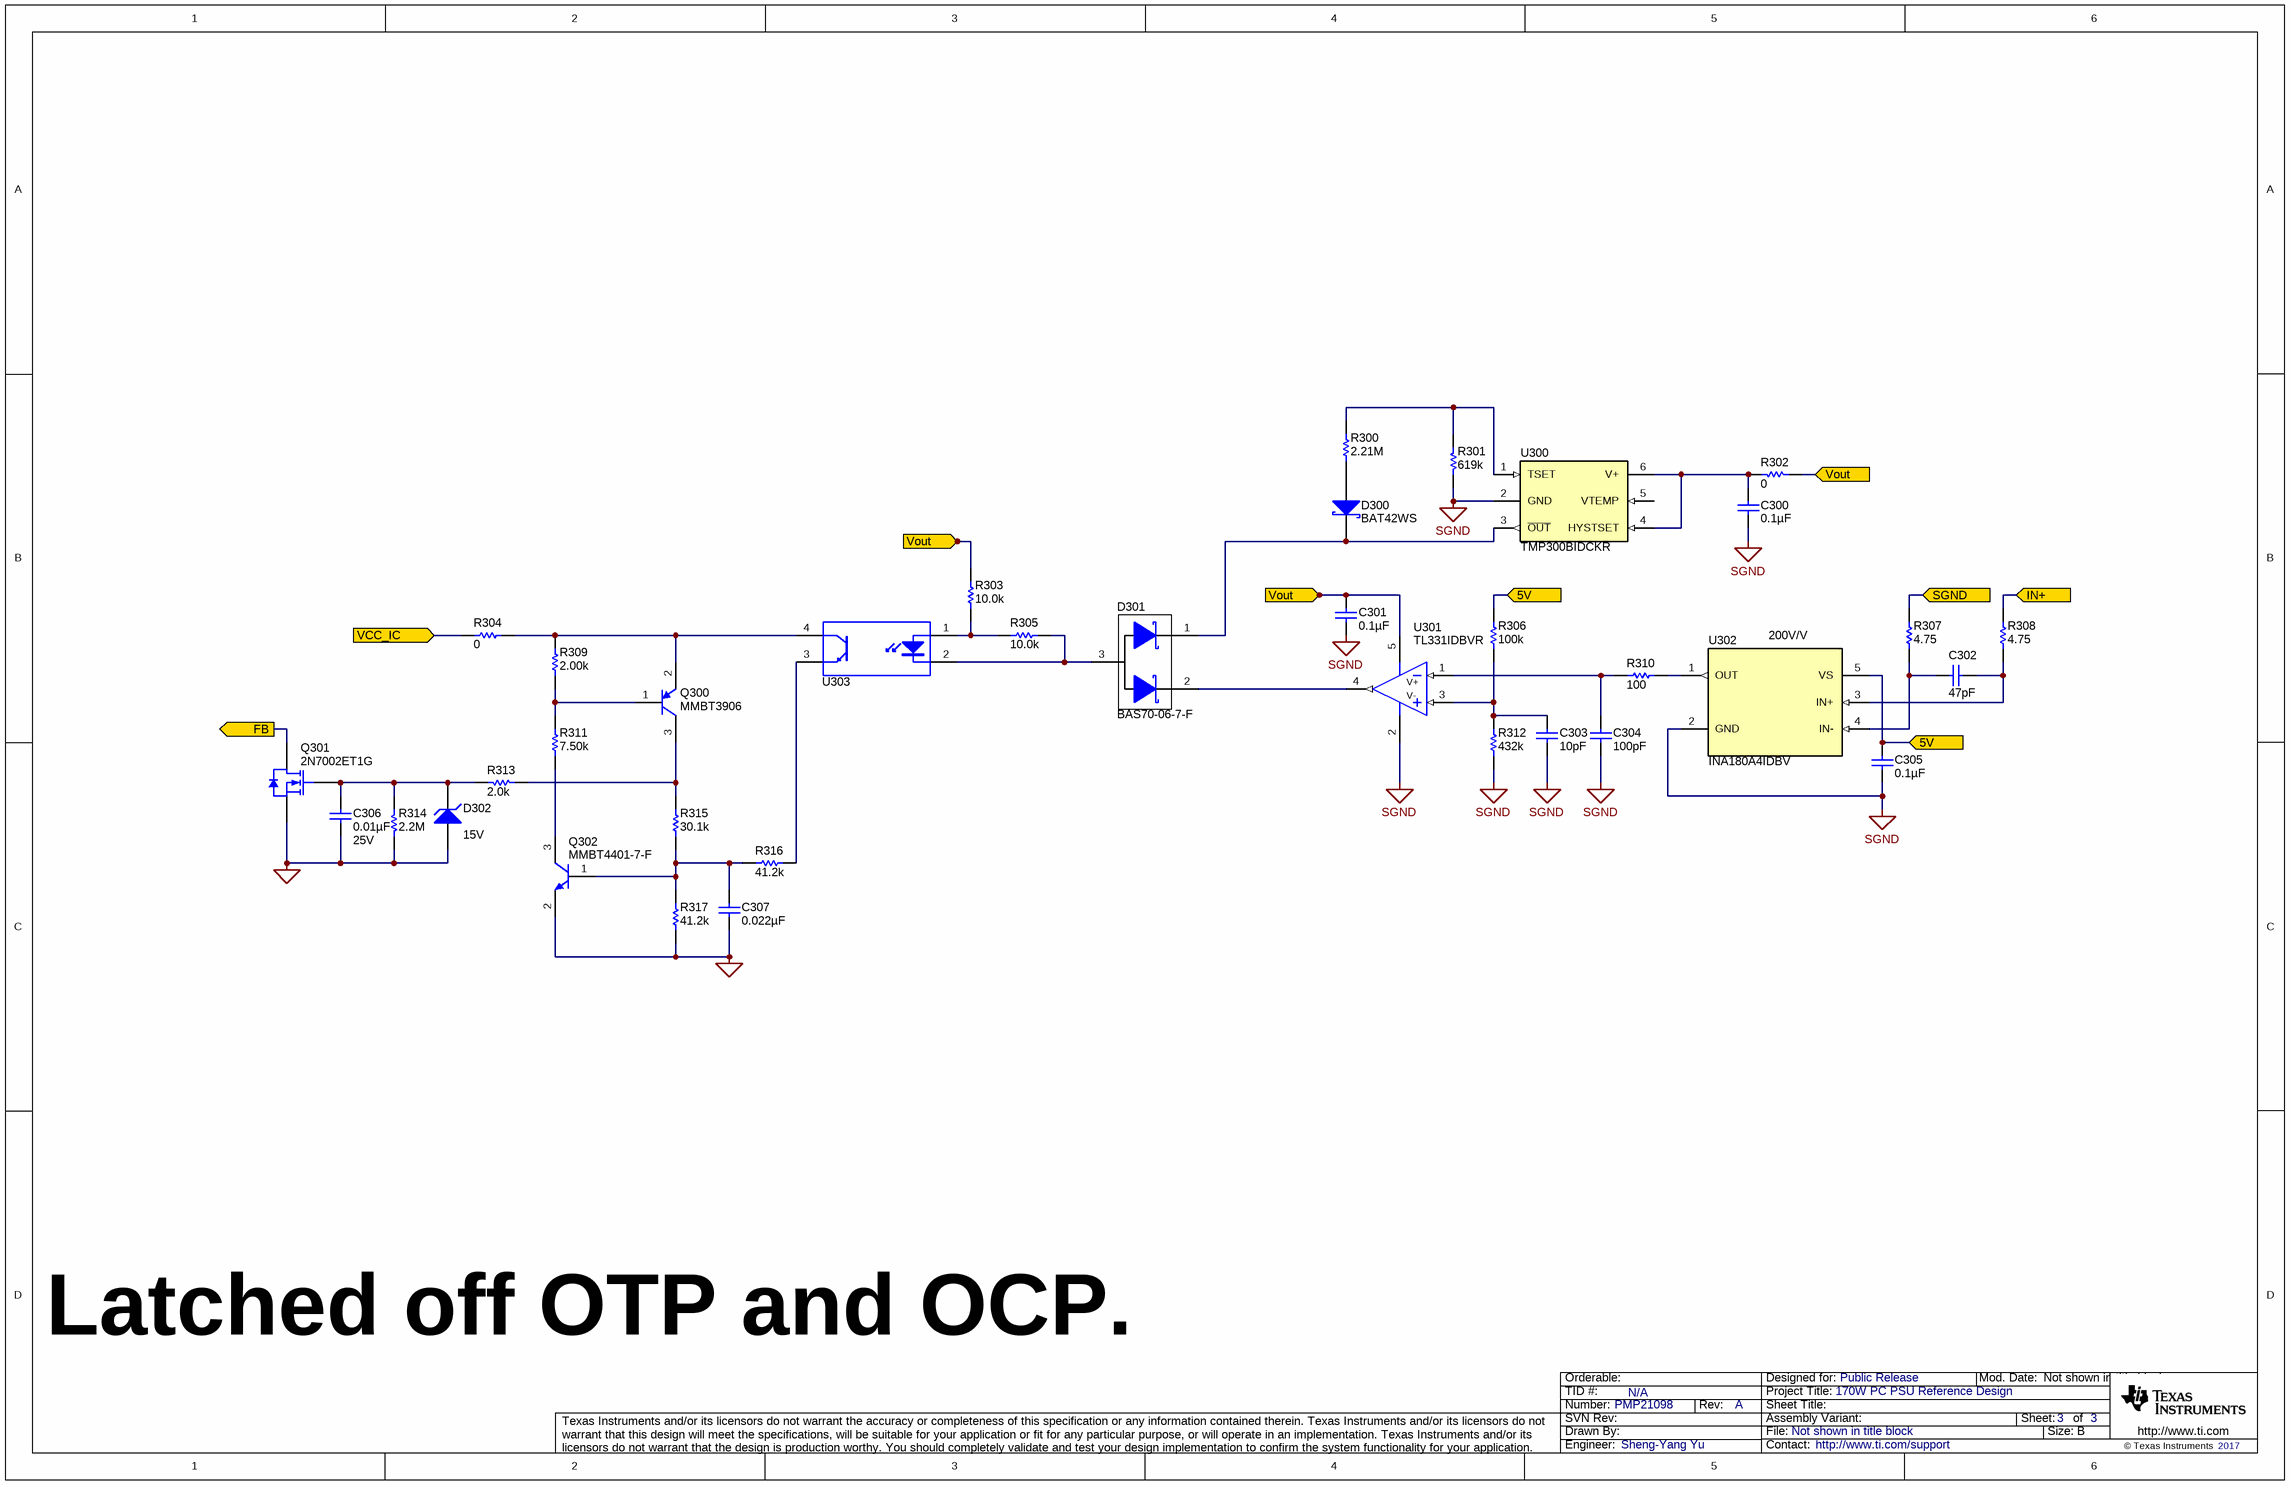
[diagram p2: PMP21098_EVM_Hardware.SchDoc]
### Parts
C300  ValueDisplayed: 0.1µF  [0402]  (hidden comment: GRM155R61C104KA88D)
C301  ValueDisplayed: 0.1µF  [0402]  (hidden comment: GRM155R61C104KA88D)
C302  ValueDisplayed: 47pF  [1206]  (hidden comment: 12067A470JAT2A)
C303  ValueDisplayed: 10pF  [0402]  (hidden comment: GRM1555C1H100RA01D)
C304  ValueDisplayed: 100pF  [0402]  (hidden comment: GRM1555C1H101JA01D)
C305  ValueDisplayed: 0.1µF  [0402]  (hidden comment: GRM155R61E104KA87D)
C306  ValueDisplayed: 0.01µF  Value2: 25V  [0603]  (hidden comment: C0603C103J3GECAUTO)
C307  ValueDisplayed: 0.022µF  [0603]  (hidden comment: C0603C223K5RACTU)
D300  BAT42WS  [sod-323]
D301  BAS70-06-7-F  [SOT-23]
D302  value 15V  [SOD-523]  (hidden comment: MM5Z15VT1G)
Q300  MMBT3906  [SOT-23]
Q301  2N7002ET1G  [SOT-23]
Q302  MMBT4401-7-F  [SOT-23]
R300  ValueDisplayed: 2.21M  [0603]  (hidden comment: CRCW06032M21FKEA)
R301  value 619k  [0402]  (hidden comment: CRCW0402619KFKED)
R302  value 0  [0402]  (hidden comment: ERJ-2GE0R00X)
R303  ValueDisplayed: 10.0k  [0603]  (hidden comment: CRCW060310K0FKEA)
R304  ValueDisplayed: 0  [0603]  (hidden comment: CRCW06030000Z0EA)
R305  ValueDisplayed: 10.0k  [0603]  (hidden comment: CRCW060310K0FKEA)
R306  ValueDisplayed: 100k  [0402]  (hidden comment: CRCW0402100KFKED)
R307  ValueDisplayed: 4.75  [0402]  (hidden comment: CRCW04024R75FKED)
R308  ValueDisplayed: 4.75  [0402]  (hidden comment: CRCW04024R75FKED)
R309  ValueDisplayed: 2.00k  [CPF0603]  (hidden comment: CPF0603B2K0E)
R310  ValueDisplayed: 100  [0402]  (hidden comment: ATC504L1000FTNCFT)
R311  ValueDisplayed: 7.50k  [0603]  (hidden comment: RC0603FR-077K5L)
R312  ValueDisplayed: 432k  [0603]  (hidden comment: CRCW0603432KFKEA)
R313  ValueDisplayed: 2.0k  [0603]  (hidden comment: RC0603JR-072KL)
R314  ValueDisplayed: 2.2M  [0603]  (hidden comment: CRCW06032M20JNEA)
R315  ValueDisplayed: 30.1k  [0603]  (hidden comment: CRCW060330K1FKEA)
R316  ValueDisplayed: 41.2k  [0603]  (hidden comment: CRCW060341K2FKEA)
R317  ValueDisplayed: 41.2k  [0603]  (hidden comment: CRCW060341K2FKEA)
U300  TMP300BIDCKR  [DCK0006A_N]
U301  TL331IDBVR  [DBV0005A_N]
U302  INA180A4IDBV  [DBV0005A_N]
U303  FOD817D  [DIP-4]  (value not drawn)

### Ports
5V (in), FB (out), IN+ (in), SGND (in), VCC_IC (in), Vout (in)

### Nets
GND: C306.2 C307.2 D302.2(A) Q301.2(S) Q302.2(E) R314.1 R317.1
SGND: C300.2 C301.2 C303.2 C304.2 C305.2 R301.1 R307.2 R312.1 U300.2(GND) U301.2(V-/GND) U302.2(GND) ; port SGND
5V: C305.1 R306.2 U302.5(VS) ; port 5V
FB: Q301.3(D) ; port FB
IN+: R308.2 ; port IN+
VCC_IC: R304.1 ; port VCC_IC
Vout: C301.1 R302.1 R303.2 U301.5(V+) ; port Vout
NetC300_1: C300.1 R302.2 U300.4(HYSTSET) U300.6(V+)
NetC302_1: C302.1 R308.1 U302.3(IN+)
NetC302_2: C302.2 R307.1 U302.4(IN-)
NetC303_1: C303.1 R306.1 R312.2 U301.3(IN+)
NetC304_1: C304.1 R310.2 U301.1(IN-)
NetC306_1: C306.1 D302.1(K) Q301.1(G) R313.2 R314.2
NetC307_1: C307.1 Q302.1(B) R315.1 R316.1 R317.2
NetD300_1: D300.1(K) D301.1(A) U300.3(~{OUT})
NetD300_2: D300.2(A) R300.1
NetD301_2: D301.2(K) U301.4(OUT)
NetD301_3: D301.3(A) R305.1 U303.2(K)
NetQ300_1: Q300.1(B) R309.1 R311.2
NetQ300_2: Q300.2(E) R304.2 R309.2 U303.4(C)
NetQ300_3: Q300.3(C) R313.1 R315.2
NetQ302_3: Q302.3(C) R311.1
NetR300_2: R300.2 R301.2 U300.1(TSET)
NetR303_1: R303.1 R305.2 U303.1(A)
NetR310_1: R310.1 U302.1(OUT)
NetR316_2: R316.2 U303.3(E)

Not connected (* = marked no-connect by the designer): U300 5(VTEMP)

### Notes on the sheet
- (near U302) 200V/V
- Latched off OTP and OCP.

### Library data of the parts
C300 C301 = GRM155R61C104KA88D: CAP, CERM, 0.1uF, 16V, +/-10%, X5R, 0402; Manufacturer: MuRata; Polarized: N; CompType: Capacitor; U/M: EA; Cap_F: 0.0000001; Tolerance_%: 10; Value1: Unknown; VDC_V: 16; TaMin_C: -55; TaMax_C: 85
C302 = 12067A470JAT2A: CAP, CERM, 47 pF, 500 V,+/- 5%, C0G/NP0, 1206; Manufacturer: AVX; Polarized: N; CompType: Capacitor; Value: 47pF; U/M: EA; Cap_F: 0.000000000047; Tolerance_%: 5; VDC_V: 500; Value2: 500V; TaMin_C: -55; TaMax_C: 125; SizeArea_mm2: 5.12; SizeAreaWB_mm2: 10.92; SizeX_mm: 3.2; SizeY_mm: 1.6; SizeZ_mm: 1.35; AEC Category: Q200; Green_Lifecycle: Not Set; Green_REACh: Incomplete
C303 = GRM1555C1H100RA01D: CAP, CERM, 10 pF, 50 V,+/- 4%, C0G/NP0, 0402; Manufacturer: MuRata; Polarized: N; CompType: Capacitor; Value: 10pF; U/M: EA; Cap_F: 0.00000000001; Tolerance_%: 4; VDC_V: 50; Value2: 50V; TaMin_C: -55; TaMax_C: 125; SizeArea_mm2: 0.5; SizeAreaWB_mm2: 3; SizeX_mm: 1; SizeZ_mm: 0.6; AEC Category: Q200
C304 = GRM1555C1H101JA01D: CAP, CERM, 100 pF, 50 V,+/- 5%, C0G/NP0, 0402; Manufacturer: MuRata; Polarized: N; CompType: Capacitor; Value: 100pF; U/M: EA; Cap_F: 0.0000000001; Tolerance_%: 5; VDC_V: 50; Value2: 50V; TaMin_C: -55; TaMax_C: 125; SizeArea_mm2: 0.5; SizeAreaWB_mm2: 3; SizeX_mm: 1; SizeZ_mm: 0.6; AEC Category: Q200; Green_Lifecycle: Active; Green_REACh: Passed
C305 = GRM155R61E104KA87D: CAP, CERM, 0.1 µF, 25 V, +/- 10%, X5R, 0402; Manufacturer: MuRata; Polarized: N; CompType: Capacitor; Value: 0.1uF; U/M: EA; Cap_F: 0.0000001; Tolerance_%: 10; Value1: Unknown; VDC_V: 25; Value2: 25V; TaMin_C: -55; TaMax_C: 85
C306 = C0603C103J3GECAUTO: CAP, CERM, 0.01 µF, 25 V,+/- 5%, C0G/NP0, AEC-Q200 Grade 1, 0603; Manufacturer: Kemet; Polarized: N; CompType: Capacitor; Value: 0.01uF; U/M: EA; Cap_F: 0.00000001; Tolerance_%: 5; VDC_V: 25; TaMin_C: -55; TaMax_C: 125; SizeArea_mm2: 1.28; SizeAreaWB_mm2: 4.68; SizeX_mm: 1.6; SizeY_mm: 0.8; SizeZ_mm: 1; AEC Category: Q200; AEC Qualified: Y
C307 = C0603C223K5RACTU: CAP, CERM, 0.022 µF, 50 V,+/- 10%, X7R, 0603; Manufacturer: Kemet; Polarized: N; CompType: Capacitor; Value: 0.022uF; U/M: EA; Cap_F: 0.000000022; Tolerance_%: 10; VDC_V: 50; Value2: 50V; TaMin_C: -55; TaMax_C: 125; SizeArea_mm2: 1.28; SizeAreaWB_mm2: 4.68; SizeX_mm: 1.6; SizeY_mm: 0.8; SizeZ_mm: 1; AEC Category: Q200; Green_Lifecycle: Active; Green_REACh: Passed
D300 = BAT42WS-7-F: Diode, Schottky, 30V, 0.2A, SOD-323; Manufacturer: Diodes Inc.; Value: 1V; U/M: EA; Vf_V: 1; Io_A: 0.2; Vr_V: 30
D301 = BAS70-06-7-F: Diode, Schottky, 70 V, 0.07 A, SOT-23; Manufacturer: Diodes Inc.; SymbolCreator: a0412235; U/M: EA; Vf_V: 1.7; Value: 70V; Value1: 0.07A; Value2: 1.7V; Io_A: 0.07; Vr_V: 70; SizeAreaWB_mm2: 14; SizeArea_mm2: 7.5; SizeX_mm: 2.5; SizeY_mm: 3; SizeZ_mm: 1.1; AEC Category: Q101; Green_Lifecycle: Not Set; Green_REACh: Incomplete
D302 = MM5Z5V6ST1G: DIODE ZENER 15V 200MW SOD523; Manufacturer: ON Semiconductor; SymbolCreator: a0412235; U/M: EA; Power_W: 0.5; Vz_V: 15; Value1: 0.5W; RJA_CperW: 250; SizeAreaWB_mm2: 5.13; SizeArea_mm2: 1.53; SizeX_mm: 1.7; SizeY_mm: 0.9; SizeZ_mm: 0.65; AEC Category: Q101
Q300 = MMBT3906, Fairchild Semiconductor: Transistor, PNP, 40 V, 0.2 A, SOT-23; CompType: BJT; PNP: 1; NPN: 0; Vceo_V: 40; Vcesat1_V: 0.25; Value: 40 V; IcRated_A: 0.2; Value1: 0.2 A; HfeMax: 300; TaMin_C: -55; TaMax_C: 150; SizeAreaWB_mm2: 14; SizeArea_mm2: 7.5; SizeX_mm: 2.5; SizeY_mm: 3; SizeZ_mm: 1.1; U/M: EA; AEC Category: Q101; Green_Lifecycle: Active; Green_REACh: Passed
Q301 = 2N7002ET1G: MOSFET, N-CH, 60V, 0.26A, SOT-23; Manufacturer: ON Semiconductor; Alternate Manufacturer: None; U/M: EA; ChType: N; VdsMax_V: 60; Value1: 3 ohm; Rdson45_Ohm: 3; Value2: 0.81 nC; QgTyp_nC: 0.81; Vgs_V: 20; IdsMax_A: 0.26
Q302 = MMBT4401-7-F, Diodes Inc.: Transistor, NPN, 40 V, 0.15 A, SOT-23; CompType: BJT; PNP: 0; NPN: 1; Vceo_V: 40; Vcesat1_V: 0.4; Value: 40 V; IcRated_A: 0.15; Value1: 0.15 A; HfeMax: 300; TaMin_C: -55; TaMax_C: 150; SizeAreaWB_mm2: 14; SizeArea_mm2: 7.5; SizeX_mm: 2.5; SizeY_mm: 3; SizeZ_mm: 1.1; U/M: EA; AEC Category: Q101; Green_Lifecycle: Active; Green_REACh: Passed
R300 = CRCW06032M21FKEA: RES, 2.21 M, 1%, 0.1 W, 0603; Manufacturer: Vishay-Dale; CompType: Resistor; Value: 2.21Meg; Res_ohm: 2210000; Value_Code: 2M21; Tolerance_%: 1; Power_W: 0.1; Value2: 0.1W; VDC_V: 75; TempCo: 100 ppm/C; SizeArea_mm2: 1.28; SizeX_mm: 1.6; SizeY_mm: 0.8; EIA_Code: E96; U/M: EA; AEC Category: Q200
R301 = CRCW0402619KFKED: RES, 619k ohm, 1%, 0.063W, 0402; Manufacturer: Vishay-Dale; CompType: Resistor; Res_ohm: 619000; Tolerance_%: 1; Power_W: 0.063; VDC_V: 50; TempCo: 100 ppm/C; EIA_Code: E96; U/M: EA
R302 = ERJ-2GE0R00X: RES, 0 ohm, 5%, 0.063W, 0402; Manufacturer: Panasonic; CompType: Resistor; Value_Code: 0000; Tolerance_%: 5; Power_W: 0.063; VDC_V: 50; TempCo: 600 ppm/C; EIA_Code: E24; U/M: EA
R303 R305 = CRCW060310K0FKEA: RES, 10.0 k, 1%, 0.1 W, 0603; Manufacturer: Vishay-Dale; CompType: Resistor; Value: 10.0k; Res_ohm: 10000; Value_Code: 10k0; Tolerance_%: 1; Power_W: 0.1; Value2: 0.1W; VDC_V: 75; TempCo: 100 ppm/C; SizeArea_mm2: 1.28; SizeX_mm: 1.6; SizeY_mm: 0.8; EIA_Code: E96; U/M: EA; AEC Category: Q200; Green_Lifecycle: Active; Green_REACh: Passed
R304 = CRCW06030000Z0EA: as R202 on sheet PMP21098_BlankSheet
R306 = CRCW0402100KFKED: RES, 100 k, 1%, 0.063 W, 0402; Manufacturer: Vishay-Dale; CompType: Resistor; Value: 100k; Res_ohm: 100000; Tolerance_%: 1; Power_W: 0.063; Value2: 0.063W; VDC_V: 50; TempCo: 100 ppm/C; SizeArea_mm2: 0.5; SizeZ_mm: 0.6; EIA_Code: E96; U/M: EA; AEC Category: Q200; Green_Lifecycle: Active; Green_REACh: Passed
R307 R308 = CRCW04024R75FKED: RES, 4.75, 1%, 0.063 W, 0402; Manufacturer: Vishay-Dale; CompType: Resistor; Value: 4.75; Value_Code: 4R75; Tolerance_%: 1; Power_W: 0.063; Value2: 0.063W; VDC_V: 50; TempCo: 100 ppm/C; SizeArea_mm2: 0.5; SizeZ_mm: 0.6; EIA_Code: E96; U/M: EA; AEC Category: Q200
R309 = CPF0603B2K0E: RES, 2.00 k, 0.1%, 0.063 W, 0603; Manufacturer: TE Connectivity; CompType: Resistor; Value: 2.00k; Res_ohm: 2000; Value_Code: 2k00; Tolerance_%: 0.1; Power_W: 0.063; Value2: 0.063W; VDC_V: 50; TempCo: 25 ppm/C; SizeArea_mm2: 1.24; SizeX_mm: 1.55; SizeY_mm: 0.8; SizeZ_mm: 0.55; EIA_Code: E192; U/M: EA; AEC Category: Q200; AEC Qualified: N; Green_Lifecycle: Active; Green_REACh: Passed
R310 = ATC504L1000FTNCFT: RES, 100, 1%, 0.125 W, AEC-Q200 Grade 1, 0402; Manufacturer: AT Ceramics; CompType: Resistor; Value: 100; Value_Code: 100R; Tolerance_%: 1; Power_W: 0.125; Value2: 0.125W; TempCo: ppm/C; SizeArea_mm2: 0.5; SizeZ_mm: 0.6; EIA_Code: E96; U/M: EA; AEC Category: Q200; AEC Qualified: Y
R311 = RC0603FR-077K5L: RES, 7.50 k, 1%, 0.1 W, 0603; Manufacturer: Yageo America; CompType: Resistor; Value: 7.50k; Res_ohm: 7500; Value_Code: 7k50; Tolerance_%: 1; Power_W: 0.1; Value2: 0.1W; VDC_V: 150; TempCo: 200 ppm/C; SizeArea_mm2: 1.28; SizeX_mm: 1.6; SizeY_mm: 0.8; EIA_Code: E96; U/M: EA; AEC Category: Q200; Green_Lifecycle: Active; Green_REACh: Passed
R312 = CRCW0603432KFKEA: RES, 432 k, 1%, 0.1 W, 0603; Manufacturer: Vishay-Dale; CompType: Resistor; Value: 432k; Res_ohm: 432000; Tolerance_%: 1; Power_W: 0.1; Value2: 0.1W; VDC_V: 75; TempCo: 100 ppm/C; SizeArea_mm2: 1.28; SizeX_mm: 1.6; SizeY_mm: 0.8; EIA_Code: E96; U/M: EA; AEC Category: Q200; Green_Lifecycle: Active; Green_REACh: Passed
R313 = RC0603JR-072KL: RES, 2.0 k, 5%, 0.1 W, 0603; Manufacturer: Yageo America; CompType: Resistor; Value: 2.0k; Res_ohm: 2000; Value_Code: 2k00; Tolerance_%: 5; Power_W: 0.1; Value2: 0.1W; VDC_V: 50; TempCo: 100 ppm/C; SizeArea_mm2: 1.28; SizeX_mm: 1.6; SizeY_mm: 0.8; SizeZ_mm: 1; EIA_Code: E24; U/M: EA; AEC Category: Q200; Green_Lifecycle: Active; Green_REACh: Passed
R314 = CRCW06032M20JNEA: RES, 2.2 M, 5%, 0.1 W, 0603; Manufacturer: Vishay-Dale; CompType: Resistor; Value: 2.2Meg; Res_ohm: 2200000; Value_Code: 2M20; Tolerance_%: 5; Power_W: 0.1; Value2: 0.1W; VDC_V: 75; TempCo: 200 ppm/C; SizeArea_mm2: 1.28; SizeX_mm: 1.6; SizeY_mm: 0.8; SizeZ_mm: 1; EIA_Code: E24; U/M: EA; AEC Category: Q200
R315 = CRCW060330K1FKEA: RES, 30.1 k, 1%, 0.1 W, 0603; Manufacturer: Vishay-Dale; CompType: Resistor; Value: 30.1k; Res_ohm: 30100; Value_Code: 30k1; Tolerance_%: 1; Power_W: 0.1; Value2: 0.1W; VDC_V: 75; TempCo: 100 ppm/C; SizeArea_mm2: 1.28; SizeX_mm: 1.6; SizeY_mm: 0.8; EIA_Code: E96; U/M: EA; AEC Category: Q200; Green_Lifecycle: Active; Green_REACh: Passed
R316 R317 = CRCW060341K2FKEA: RES, 41.2 k, 1%, 0.1 W, 0603; Manufacturer: Vishay-Dale; CompType: Resistor; Value: 41.2k; Res_ohm: 41200; Value_Code: 41k2; Tolerance_%: 1; Power_W: 0.1; Value2: 0.1W; VDC_V: 75; TempCo: 100 ppm/C; SizeArea_mm2: 1.28; SizeX_mm: 1.6; SizeY_mm: 0.8; EIA_Code: E96; U/M: EA; AEC Category: Q200
U300 = TMP300BIDCKR: Resistor-Programmable, up to 18V-Capable Temp Switch and Analog Out Sensor, DCK0006A (SOT-SC70-6); Alternate PartNumber: TMP300BIDCKT; Manufacturer: Texas Instruments; SymbolCreator: a0412235; SizeArea_mm2: 4.2; SizeAreaWB_mm2: 9.3; SizeX_mm: 2.1; SizeY_mm: 2; SizeZ_mm: 1.1; CompType: IC; U/M: EA; Green_Lifecycle: Active; Green_REACh: Passed
U301 = TL331IDBVR: SINGLE DIFFERENTIAL COMPARATOR, DBV0005A (SOT-23-5); Alternate PartNumber: TL331IDBVT; Manufacturer: Texas Instruments; SymbolCreator: a0411947; SizeArea_mm2: 8.12; SizeAreaWB_mm2: 14.82; SizeX_mm: 2.8; SizeY_mm: 2.9; SizeZ_mm: 1.45; CompType: IC; U/M: EA; Green_Lifecycle: Active; Green_REACh: Passed
U302 = INA180A4IDBV: Low- and High-Side Measurement, Multichannel, Voltage Output, Current-Sense Amplifier, DBV0005A (SOT-23-5); Manufacturer: Texas Instruments; SymbolCreator: a0411947; SizeArea_mm2: 8.12; SizeAreaWB_mm2: 14.82; SizeX_mm: 2.8; SizeY_mm: 2.9; SizeZ_mm: 1.45; CompType: IC; U/M: EA
U303 = FOD817A: OPTOISOLATOR 5KV TRANSISTOR 4DIP; Manufacturer: Fairchild Semiconductor; CTR (Min): 300%; CTR (Max): 600%; Voltage_Isolation_Vrms: 5000V; CompType: Optocoupler; SizeAreaWB_mm2: 71.064; SizeArea_mm2: 40.304; SizeX_mm: 8.8; SizeY_mm: 4.58; SizeZ_mm: 5

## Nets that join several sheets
GND: PMP21098_CoverSheet (23 pins), PMP21098_BlankSheet (24 pins), PMP21098_EVM_Hardware (7 pins)
SGND: PMP21098_BlankSheet (23 pins), PMP21098_EVM_Hardware (11 pins)
5V: PMP21098_BlankSheet (C200.1 U200.5), PMP21098_EVM_Hardware (C305.1 R306.2 U302.5)
FB: PMP21098_BlankSheet (C225.1 D206.2 U203.5 U204.4), PMP21098_EVM_Hardware (Q301.3)
HV: PMP21098_CoverSheet (C103.1 D100.4 R106.2), PMP21098_BlankSheet (C201.1 Q200.4 R214.2)
IN+: PMP21098_BlankSheet (7 pins), PMP21098_EVM_Hardware (R308.2)
RVCC: PMP21098_CoverSheet (5 pins), PMP21098_BlankSheet (8 pins)
VCC: PMP21098_CoverSheet (R120.1), PMP21098_BlankSheet (C223.2 D205.2 R231.1)
VCC_IC: PMP21098_BlankSheet (C224.2 C226.1 D205.1 U203.3), PMP21098_EVM_Hardware (R304.1)
Vout: PMP21098_BlankSheet (20 pins), PMP21098_EVM_Hardware (C301.1 R302.1 R303.2 U301.5)
XCAP: PMP21098_CoverSheet (D106.1 D107.1), PMP21098_BlankSheet (R217.2)

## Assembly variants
001: not fitted C115 C122 C123 C218 C219 C220 C221 C222 C227 C229 D108 R112 R113 R120 R121 R312 U101 U203 U204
